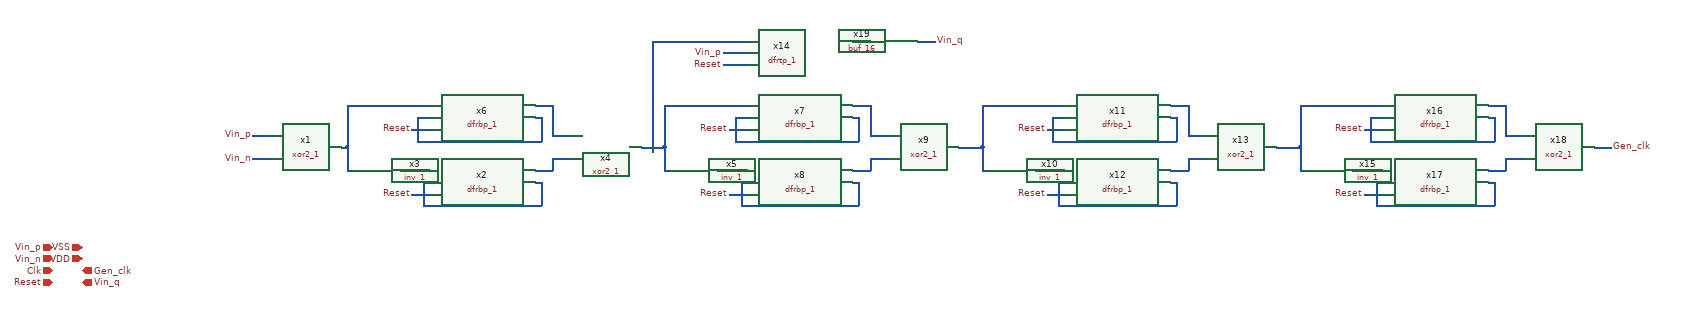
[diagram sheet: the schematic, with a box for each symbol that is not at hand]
v {xschem version=3.0.0 file_version=1.2 }
G {}
K {}
V {}
S {}
E {}
N 420 -290 450 -290 {
lab=#net1}
N 420 -250 450 -250 {
lab=#net2}
N 690 -190 720 -190 {
lab=Reset}
N 690 -300 720 -300 {
lab=Reset}
N 570 -270 580 -270 {
lab=#net3}
N 580 -340 580 -270 {
lab=#net3}
N 580 -340 720 -340 {
lab=#net3}
N 580 -270 580 -240 {
lab=#net3}
N 580 -240 580 -230 {
lab=#net3}
N 900 -320 910 -320 {
lab=#net4}
N 710 -210 720 -210 {
lab=#net5}
N 900 -230 910 -230 {
lab=#net6}
N 700 -320 720 -320 {
lab=#net4}
N 900 -340 930 -340 {
lab=#net7}
N 930 -340 930 -290 {
lab=#net7}
N 930 -290 960 -290 {
lab=#net7}
N 910 -230 930 -230 {
lab=#net6}
N 930 -250 930 -230 {
lab=#net6}
N 930 -250 960 -250 {
lab=#net6}
N 1080 -270 1110 -270 {
lab=#net8}
N 910 -320 910 -290 {
lab=#net4}
N 910 -290 910 -280 {
lab=#net4}
N 700 -280 910 -280 {
lab=#net4}
N 700 -320 700 -280 {
lab=#net4}
N 670 -230 720 -230 {
lab=#net9}
N 900 -210 910 -210 {
lab=#net5}
N 910 -210 910 -170 {
lab=#net5}
N 710 -170 910 -170 {
lab=#net5}
N 710 -210 710 -170 {
lab=#net5}
N 580 -230 590 -230 {
lab=#net3}
N 1230 -190 1260 -190 {
lab=Reset}
N 1230 -300 1260 -300 {
lab=Reset}
N 1110 -270 1120 -270 {
lab=#net8}
N 1120 -340 1120 -270 {
lab=#net8}
N 1120 -340 1260 -340 {
lab=#net8}
N 1120 -270 1120 -240 {
lab=#net8}
N 1120 -240 1120 -230 {
lab=#net8}
N 1440 -320 1450 -320 {
lab=#net10}
N 1250 -210 1260 -210 {
lab=#net11}
N 1440 -230 1450 -230 {
lab=#net12}
N 1240 -320 1260 -320 {
lab=#net10}
N 1440 -340 1470 -340 {
lab=#net13}
N 1470 -340 1470 -290 {
lab=#net13}
N 1470 -290 1500 -290 {
lab=#net13}
N 1450 -230 1470 -230 {
lab=#net12}
N 1470 -250 1470 -230 {
lab=#net12}
N 1470 -250 1500 -250 {
lab=#net12}
N 1620 -270 1650 -270 {
lab=#net14}
N 1450 -320 1450 -290 {
lab=#net10}
N 1450 -290 1450 -280 {
lab=#net10}
N 1240 -280 1450 -280 {
lab=#net10}
N 1240 -320 1240 -280 {
lab=#net10}
N 1210 -230 1260 -230 {
lab=#net15}
N 1440 -210 1450 -210 {
lab=#net11}
N 1450 -210 1450 -170 {
lab=#net11}
N 1250 -170 1450 -170 {
lab=#net11}
N 1250 -210 1250 -170 {
lab=#net11}
N 1120 -230 1130 -230 {
lab=#net8}
N 1770 -190 1800 -190 {
lab=Reset}
N 1770 -300 1800 -300 {
lab=Reset}
N 1650 -270 1660 -270 {
lab=#net14}
N 1660 -340 1660 -270 {
lab=#net14}
N 1660 -340 1800 -340 {
lab=#net14}
N 1660 -270 1660 -240 {
lab=#net14}
N 1660 -240 1660 -230 {
lab=#net14}
N 1980 -320 1990 -320 {
lab=#net16}
N 1790 -210 1800 -210 {
lab=#net17}
N 1980 -230 1990 -230 {
lab=#net18}
N 1780 -320 1800 -320 {
lab=#net16}
N 1980 -340 2010 -340 {
lab=#net19}
N 2010 -340 2010 -290 {
lab=#net19}
N 2010 -290 2040 -290 {
lab=#net19}
N 1990 -230 2010 -230 {
lab=#net18}
N 2010 -250 2010 -230 {
lab=#net18}
N 2010 -250 2040 -250 {
lab=#net18}
N 2160 -270 2190 -270 {
lab=#net20}
N 1990 -320 1990 -290 {
lab=#net16}
N 1990 -290 1990 -280 {
lab=#net16}
N 1780 -280 1990 -280 {
lab=#net16}
N 1780 -320 1780 -280 {
lab=#net16}
N 1750 -230 1800 -230 {
lab=#net21}
N 1980 -210 1990 -210 {
lab=#net17}
N 1990 -210 1990 -170 {
lab=#net17}
N 1790 -170 1990 -170 {
lab=#net17}
N 1790 -210 1790 -170 {
lab=#net17}
N 1660 -230 1670 -230 {
lab=#net14}
N 1220 -410 1260 -410 {
lab=Reset}
N 1100 -450 1100 -270 {
lab=#net8}
N 1100 -450 1260 -450 {
lab=#net8}
N 1220 -430 1260 -430 {
lab=Vin_p}
N 1440 -450 1470 -450 {
lab=#net22}
N 2310 -190 2340 -190 {
lab=Reset}
N 2310 -300 2340 -300 {
lab=Reset}
N 2190 -270 2200 -270 {
lab=#net20}
N 2200 -340 2200 -270 {
lab=#net20}
N 2200 -340 2340 -340 {
lab=#net20}
N 2200 -270 2200 -240 {
lab=#net20}
N 2200 -240 2200 -230 {
lab=#net20}
N 2520 -320 2530 -320 {
lab=#net23}
N 2330 -210 2340 -210 {
lab=#net24}
N 2520 -230 2530 -230 {
lab=#net25}
N 2320 -320 2340 -320 {
lab=#net23}
N 2520 -340 2550 -340 {
lab=#net26}
N 2550 -340 2550 -290 {
lab=#net26}
N 2550 -290 2580 -290 {
lab=#net26}
N 2530 -230 2550 -230 {
lab=#net25}
N 2550 -250 2550 -230 {
lab=#net25}
N 2550 -250 2580 -250 {
lab=#net25}
N 2700 -270 2730 -270 {
lab=Gen_clk}
N 2530 -320 2530 -290 {
lab=#net23}
N 2530 -290 2530 -280 {
lab=#net23}
N 2320 -280 2530 -280 {
lab=#net23}
N 2320 -320 2320 -280 {
lab=#net23}
N 2290 -230 2340 -230 {
lab=#net27}
N 2520 -210 2530 -210 {
lab=#net24}
N 2530 -210 2530 -170 {
lab=#net24}
N 2330 -170 2530 -170 {
lab=#net24}
N 2330 -210 2330 -170 {
lab=#net24}
N 2200 -230 2210 -230 {
lab=#net20}
N 1550 -450 1580 -450 {
lab=Vin_q}
C {devices/title.sym} 160 30 0 0 {name=l1 author="Dr. Aubrey Beal, Dr. Phillip Bailey, Micah Tseng"
}
C {devices/ipin.sym} 80 -100 0 0 {name=p1 lab=Vin_p
}
C {devices/iopin.sym} 130 -100 0 0 {name=p2 lab=VSS
}
C {devices/opin.sym} 130 -60 0 0 {name=p3 lab=Gen_clk
}
C {devices/iopin.sym} 130 -80 0 0 {name=p4 lab=VDD
}
C {devices/ipin.sym} 80 -80 0 0 {name=p5 lab=Vin_n
}
C {devices/ipin.sym} 80 -60 0 0 {name=p6 lab=Clk
}
C {sky130_stdcells/xor2_1.sym} 510 -270 0 0 {name=x1 VGND=VSS VNB=VSS VPB=VDD VPWR=VDD prefix=sky130_fd_sc_hd__ 
}
C {devices/ipin.sym} 80 -40 0 0 {name=p7 lab=Reset
}
C {devices/lab_pin.sym} 420 -290 0 0 {name=l2 sig_type=std_logic lab=Vin_p
}
C {devices/lab_pin.sym} 420 -250 0 0 {name=l3 sig_type=std_logic lab=Vin_n
}
C {devices/lab_pin.sym} 690 -190 0 0 {name=l4 sig_type=std_logic lab=Reset
}
C {devices/lab_pin.sym} 690 -300 0 0 {name=l5 sig_type=std_logic lab=Reset
}
C {sky130_stdcells/inv_1.sym} 630 -230 0 0 {name=x3 VGND=VSS VNB=VSS VPB=VDD VPWR=VDD prefix=sky130_fd_sc_hd__ 
}
C {sky130_stdcells/dfrbp_1.sym} 810 -320 0 0 {name=x6 VGND=VSS VNB=VSS VPB=VDD VPWR=VDD prefix=sky130_fd_sc_hd__ 
}
C {sky130_stdcells/dfrbp_1.sym} 810 -210 0 0 {name=x2 VGND=VSS VNB=VSS VPB=VDD VPWR=VDD prefix=sky130_fd_sc_hd__ 
}
C {sky130_stdcells/xor2_1.sym} 1020 -270 0 0 {name=x4 VGND=VSS VNB=VSS VPB=VDD VPWR=VDD prefix=sky130_fd_sc_hd__ 
}
C {devices/opin.sym} 130 -40 0 0 {name=p8 lab=Vin_q
}
C {devices/lab_pin.sym} 1230 -190 0 0 {name=l7 sig_type=std_logic lab=Reset
}
C {devices/lab_pin.sym} 1230 -300 0 0 {name=l8 sig_type=std_logic lab=Reset
}
C {sky130_stdcells/inv_1.sym} 1170 -230 0 0 {name=x5 VGND=VSS VNB=VSS VPB=VDD VPWR=VDD prefix=sky130_fd_sc_hd__ 
}
C {sky130_stdcells/dfrbp_1.sym} 1350 -320 0 0 {name=x7 VGND=VSS VNB=VSS VPB=VDD VPWR=VDD prefix=sky130_fd_sc_hd__ 
}
C {sky130_stdcells/dfrbp_1.sym} 1350 -210 0 0 {name=x8 VGND=VSS VNB=VSS VPB=VDD VPWR=VDD prefix=sky130_fd_sc_hd__ 
}
C {sky130_stdcells/xor2_1.sym} 1560 -270 0 0 {name=x9 VGND=VSS VNB=VSS VPB=VDD VPWR=VDD prefix=sky130_fd_sc_hd__ 
}
C {devices/lab_pin.sym} 1770 -190 0 0 {name=l6 sig_type=std_logic lab=Reset
}
C {devices/lab_pin.sym} 1770 -300 0 0 {name=l10 sig_type=std_logic lab=Reset
}
C {sky130_stdcells/inv_1.sym} 1710 -230 0 0 {name=x10 VGND=VSS VNB=VSS VPB=VDD VPWR=VDD prefix=sky130_fd_sc_hd__ 
}
C {sky130_stdcells/dfrbp_1.sym} 1890 -320 0 0 {name=x11 VGND=VSS VNB=VSS VPB=VDD VPWR=VDD prefix=sky130_fd_sc_hd__ 
}
C {sky130_stdcells/dfrbp_1.sym} 1890 -210 0 0 {name=x12 VGND=VSS VNB=VSS VPB=VDD VPWR=VDD prefix=sky130_fd_sc_hd__ 
}
C {sky130_stdcells/xor2_1.sym} 2100 -270 0 0 {name=x13 VGND=VSS VNB=VSS VPB=VDD VPWR=VDD prefix=sky130_fd_sc_hd__ 
}
C {sky130_stdcells/dfrtp_1.sym} 1350 -430 0 0 {name=x14 VGND=VSS VNB=VSS VPB=VDD VPWR=VDD prefix=sky130_fd_sc_hd__ 
}
C {devices/lab_pin.sym} 1220 -410 0 0 {name=l9 sig_type=std_logic lab=Reset
}
C {devices/lab_pin.sym} 1220 -430 0 0 {name=l12 sig_type=std_logic lab=Vin_p
}
C {devices/lab_pin.sym} 1580 -450 2 0 {name=l13 sig_type=std_logic lab=Vin_q
}
C {devices/lab_pin.sym} 2310 -190 0 0 {name=l14 sig_type=std_logic lab=Reset
}
C {devices/lab_pin.sym} 2310 -300 0 0 {name=l15 sig_type=std_logic lab=Reset
}
C {devices/lab_pin.sym} 2730 -270 2 0 {name=l16 sig_type=std_logic lab=Gen_clk
}
C {sky130_stdcells/inv_1.sym} 2250 -230 0 0 {name=x15 VGND=VSS VNB=VSS VPB=VDD VPWR=VDD prefix=sky130_fd_sc_hd__ 
}
C {sky130_stdcells/dfrbp_1.sym} 2430 -320 0 0 {name=x16 VGND=VSS VNB=VSS VPB=VDD VPWR=VDD prefix=sky130_fd_sc_hd__ 
}
C {sky130_stdcells/dfrbp_1.sym} 2430 -210 0 0 {name=x17 VGND=VSS VNB=VSS VPB=VDD VPWR=VDD prefix=sky130_fd_sc_hd__ 
}
C {sky130_stdcells/xor2_1.sym} 2640 -270 0 0 {name=x18 VGND=VSS VNB=VSS VPB=VDD VPWR=VDD prefix=sky130_fd_sc_hd__ 
}
C {sky130_stdcells/buf_16.sym} 1510 -450 0 0 {name=x19 VGND=VSS VNB=VSS VPB=VDD VPWR=VDD prefix=sky130_fd_sc_hd__ 
}
